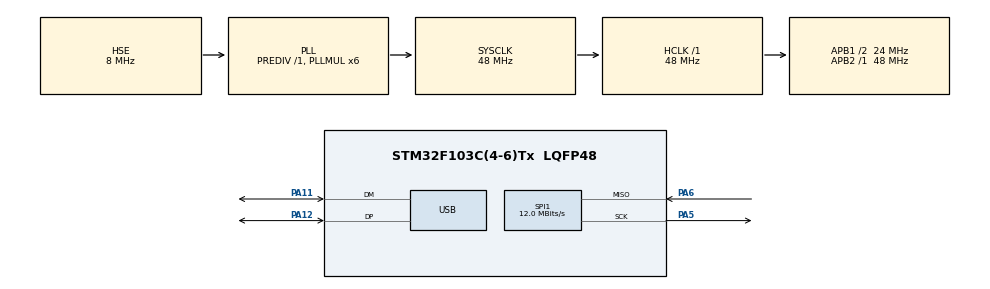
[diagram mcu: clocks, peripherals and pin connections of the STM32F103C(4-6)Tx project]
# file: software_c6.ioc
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Mcu.Family=STM32F1
Mcu.Name=STM32F103C(4-6)Tx
Mcu.Package=LQFP48
NVIC.PriorityGroup=NVIC_PRIORITYGROUP_4
NVIC.USB_LP_CAN1_RX0_IRQn=true\:0\:0\:false\:false\:true\:false\:true\:true
PA11.Mode=Device
PA11.Signal=USB_DM
PA12.Mode=Device
PA12.Signal=USB_DP
PA13.Mode=Serial_Wire
PA13.Signal=SYS_JTMS-SWDIO
PA14.Mode=Serial_Wire
PA14.Signal=SYS_JTCK-SWCLK
PA5.Mode=RX_Only_Simplex_Unidirect_Master
PA5.Signal=SPI1_SCK
PA6.Mode=RX_Only_Simplex_Unidirect_Master
PA6.Signal=SPI1_MISO
PD0-OSC_IN.Mode=HSE-External-Oscillator
PD0-OSC_IN.Signal=RCC_OSC_IN
PD1-OSC_OUT.Mode=HSE-External-Oscillator
PD1-OSC_OUT.Signal=RCC_OSC_OUT
ProjectManager.HeapSize=0x200
ProjectManager.StackSize=0x400
ProjectManager.TargetToolchain=STM32CubeIDE
RCC.AHBFreq_Value=48000000
RCC.APB1CLKDivider=RCC_HCLK_DIV2
RCC.APB1Freq_Value=24000000
RCC.APB1TimFreq_Value=48000000
RCC.APB2Freq_Value=48000000
RCC.APB2TimFreq_Value=48000000
RCC.HCLKFreq_Value=48000000
RCC.PLLMUL=RCC_PLL_MUL6
RCC.SYSCLKFreq_VALUE=48000000
RCC.SYSCLKSource=RCC_SYSCLKSOURCE_PLLCLK
RCC.USBFreq_Value=48000000
SPI1.BaudRatePrescaler=SPI_BAUDRATEPRESCALER_4
SPI1.CalculateBaudRate=12.0 MBits/s
SPI1.Direction=SPI_DIRECTION_2LINES_RXONLY
SPI1.Mode=SPI_MODE_MASTER
SPI1.VirtualType=VM_MASTER
USB_DEVICE.CLASS_NAME_FS=CUSTOM_HID
USB_DEVICE.PRODUCT_STRING_CUSTOMHID_FS=lp_keyboard
USB_DEVICE.USBD_CUSTOM_HID_REPORT_DESC_SIZE=16
USB_DEVICE.VirtualMode=CustomHid
USB_DEVICE.VirtualModeFS=Custom_Hid_FS
VP_USB_DEVICE_VS_USB_DEVICE_CUSTOM_HID_FS.Mode=CUSTOM_HID_FS
board=custom

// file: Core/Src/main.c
/* USER CODE BEGIN Header */
/**
  ******************************************************************************
  * @file           : main.c
  * @brief          : Main program body
  ******************************************************************************
  * @attention
  *
  * Copyright (c) 2022 STMicroelectronics.
  * All rights reserved.
  *
  * This software is licensed under terms that can be found in the LICENSE file
  * in the root directory of this software component.
  * If no LICENSE file comes with this software, it is provided AS-IS.
  *
  ******************************************************************************
  */
/* USER CODE END Header */
#include "main.h"
#include "usb_device.h"

/* USER CODE BEGIN Includes */
#include "keymap.h"
#include "usbd_custom_hid_if.h"
/* USER CODE END Includes */

/* USER CODE BEGIN PD */
#define CE_Pin GPIO_PIN_3
#define CE_GPIO_Port GPIOB
#define PL_Pin GPIO_PIN_4
#define PL_GPIO_Port GPIOB

#define KEY_REPORT_SIZE 16
/* USER CODE END PD */

/* USER CODE BEGIN PM */
void DelayUs(uint32_t _us)
{
    for (int i = 0; i < _us; i++)
        for (int j = 0; j < 8; j++)
            __NOP();
}
/* USER CODE END PM */

SPI_HandleTypeDef hspi1;

/* USER CODE BEGIN PV */

uint8_t spiBuffer[IO_NUMBER / 8 + 1];
uint8_t debounceBuffer[IO_NUMBER / 8 + 1];
unsigned char hidBuffer[16];
/* USER CODE END PV */

void SystemClock_Config(void);
static void MX_GPIO_Init(void);
static void MX_SPI1_Init(void);
/* USER CODE BEGIN PFP */
void ApplyDebounceFilter(uint32_t _filterTimeUs);
uint8_t* ScanKeyStates();
void keymap_t_hbuf();
/* USER CODE END PFP */

int main(void)
{
  /* USER CODE BEGIN 1 */
  HAL_RCC_DeInit();
  /* USER CODE END 1 */

  /* MCU Configuration--------------------------------------------------------*/

  /* Reset of all peripherals, Initializes the Flash interface and the Systick. */
  HAL_Init();

  /* Configure the system clock */
  SystemClock_Config();

  /* Initialize all configured peripherals */
  MX_GPIO_Init();
  MX_SPI1_Init();
  MX_USB_DEVICE_Init();

  /* Infinite loop */
  while (1)
  {

    /* USER CODE BEGIN 3 */
	  ScanKeyStates();  // Around 40us use 4MHz SPI clk
	  ApplyDebounceFilter(100);
	  keymap_t_hbuf();  // When Fn pressed use layer-2

	  // Report HID key states
	  USBD_CUSTOM_HID_SendReport_FS(hidBuffer, KEY_REPORT_SIZE);
    DelayUs(1000);
  }
  /* USER CODE END 3 */
}

void SystemClock_Config(void)
{
  RCC_OscInitTypeDef RCC_OscInitStruct = {0};
  RCC_ClkInitTypeDef RCC_ClkInitStruct = {0};
  RCC_PeriphCLKInitTypeDef PeriphClkInit = {0};

  /** Initializes the RCC Oscillators according to the specified parameters
  * in the RCC_OscInitTypeDef structure.
  */
  RCC_OscInitStruct.OscillatorType = RCC_OSCILLATORTYPE_HSE;
  RCC_OscInitStruct.HSEState = RCC_HSE_ON;
  RCC_OscInitStruct.HSEPredivValue = RCC_HSE_PREDIV_DIV1;
  RCC_OscInitStruct.HSIState = RCC_HSI_ON;
  RCC_OscInitStruct.PLL.PLLState = RCC_PLL_ON;
  RCC_OscInitStruct.PLL.PLLSource = RCC_PLLSOURCE_HSE;
  RCC_OscInitStruct.PLL.PLLMUL = RCC_PLL_MUL6;
  if (HAL_RCC_OscConfig(&RCC_OscInitStruct) != HAL_OK)
  {
    Error_Handler();
  }

  /** Initializes the CPU, AHB and APB buses clocks
  */
  RCC_ClkInitStruct.ClockType = RCC_CLOCKTYPE_HCLK|RCC_CLOCKTYPE_SYSCLK
                              |RCC_CLOCKTYPE_PCLK1|RCC_CLOCKTYPE_PCLK2;
  RCC_ClkInitStruct.SYSCLKSource = RCC_SYSCLKSOURCE_PLLCLK;
  RCC_ClkInitStruct.AHBCLKDivider = RCC_SYSCLK_DIV1;
  RCC_ClkInitStruct.APB1CLKDivider = RCC_HCLK_DIV2;
  RCC_ClkInitStruct.APB2CLKDivider = RCC_HCLK_DIV1;

  if (HAL_RCC_ClockConfig(&RCC_ClkInitStruct, FLASH_LATENCY_1) != HAL_OK)
  {
    Error_Handler();
  }
  PeriphClkInit.PeriphClockSelection = RCC_PERIPHCLK_USB;
  PeriphClkInit.UsbClockSelection = RCC_USBCLKSOURCE_PLL;
  if (HAL_RCCEx_PeriphCLKConfig(&PeriphClkInit) != HAL_OK)
  {
    Error_Handler();
  }
}

static void MX_SPI1_Init(void)
{

  /* SPI1 parameter configuration*/
  hspi1.Instance = SPI1;
  hspi1.Init.Mode = SPI_MODE_MASTER;
  hspi1.Init.Direction = SPI_DIRECTION_2LINES_RXONLY;
  hspi1.Init.DataSize = SPI_DATASIZE_8BIT;
  hspi1.Init.CLKPolarity = SPI_POLARITY_HIGH;
  hspi1.Init.CLKPhase = SPI_PHASE_1EDGE;
  hspi1.Init.NSS = SPI_NSS_SOFT;
  hspi1.Init.BaudRatePrescaler = SPI_BAUDRATEPRESCALER_16;
  hspi1.Init.FirstBit = SPI_FIRSTBIT_MSB;
  hspi1.Init.TIMode = SPI_TIMODE_DISABLE;
  hspi1.Init.CRCCalculation = SPI_CRCCALCULATION_DISABLE;
  hspi1.Init.CRCPolynomial = 10;
  if (HAL_SPI_Init(&hspi1) != HAL_OK)
  {
    Error_Handler();
  }

}

static void MX_GPIO_Init(void)
{
  GPIO_InitTypeDef GPIO_InitStruct = {0};
  /* GPIO Ports Clock Enable */
  __HAL_RCC_GPIOB_CLK_ENABLE();

  /*Configure GPIO pins : PBPin PBPin */
  GPIO_InitStruct.Pin = CE_Pin|PL_Pin;
  GPIO_InitStruct.Mode = GPIO_MODE_OUTPUT_PP;
  GPIO_InitStruct.Pull = GPIO_NOPULL;
  GPIO_InitStruct.Speed = GPIO_SPEED_FREQ_LOW;
  HAL_GPIO_Init(GPIOB, &GPIO_InitStruct);

  HAL_GPIO_WritePin(GPIOB, CE_Pin, GPIO_PIN_RESET);
}

/* USER CODE BEGIN 4 */
uint8_t* ScanKeyStates()
{
    memset(spiBuffer, 0xFF, IO_NUMBER / 8 + 1);
    PL_GPIO_Port->BSRR = PL_Pin; // Latch
    hspi1.pRxBuffPtr = (uint8_t*) spiBuffer;
    hspi1.RxXferCount = IO_NUMBER / 8 + 1;
    __HAL_SPI_ENABLE(&hspi1);
    while (hspi1.RxXferCount > 0U)
    {
        if (__HAL_SPI_GET_FLAG(&hspi1, SPI_FLAG_RXNE))
        {
            /* read the received data */
            (*(uint8_t*) hspi1.pRxBuffPtr) = *(__IO uint8_t*) &(hspi1.Instance->DR);
            hspi1.pRxBuffPtr += sizeof(uint8_t);
            hspi1.RxXferCount--;

        }
    }
    __HAL_SPI_DISABLE(&hspi1);

    PL_GPIO_Port->BRR = PL_Pin; // Sample
    return (void*)0;}

void ApplyDebounceFilter(uint32_t _filterTimeUs)
{
    memcpy(debounceBuffer, spiBuffer, IO_NUMBER / 8 + 1);

    DelayUs(_filterTimeUs);
    ScanKeyStates();

    uint8_t mask;
    for (int i = 0; i < IO_NUMBER / 8 + 1; i++)
    {
        mask = spiBuffer[i];

        mask = debounceBuffer[i] ^ spiBuffer[i];
        spiBuffer[i] |= mask;
    }
}

void keymap_t_hbuf()
{
	int16_t index, bitIndex;

	  memset(debounceBuffer, 0, IO_NUMBER / 8 + 1);
		for (int16_t i = 0; i < IO_NUMBER / 8; i++)
	    {
	        for (int16_t j = 0; j < 8; j++)
	        {
	            index = (int16_t) (leapmotor_keymap[0][i * 8 + j] / 8);
	            bitIndex = (int16_t) (leapmotor_keymap[0][i * 8 + j] % 8);
	            if (spiBuffer[index + 1] & (0x80 >> bitIndex)) // accrouding real key pressed to find
	                debounceBuffer[i] |= 0x80 >> j;
	        }
	        debounceBuffer[i] = ~debounceBuffer[i];
	    }

	    memset(hidBuffer, 0, KEY_REPORT_SIZE);
	    for (int i = 0; i < IO_NUMBER / 8; i++)
	    {
	        for (int j = 0; j < 8; j++)
	        {
	            index = (int16_t) (leapmotor_keymap[1][i * 8 + j] / 8 + 0); // +1 for modifier
	            bitIndex = (int16_t) (leapmotor_keymap[1][i * 8 + j] % 8);
	            if (bitIndex < 0)
	            {
	                index -= 1;
	                bitIndex += 8;
	            } else if (index > 100)
	                continue;

	            if (debounceBuffer[i] & (0x80 >> j))
	                hidBuffer[index+1] |= 1 << (bitIndex); // +1 for Report-ID

	        }
	    }

}
/* USER CODE END 4 */

void Error_Handler(void)
{
  __disable_irq();
  while (1)
  {
  }
}
